VERSION 5.7 ;
  NOWIREEXTENSIONATPIN ON ;
  DIVIDERCHAR "/" ;
  BUSBITCHARS "[]" ;
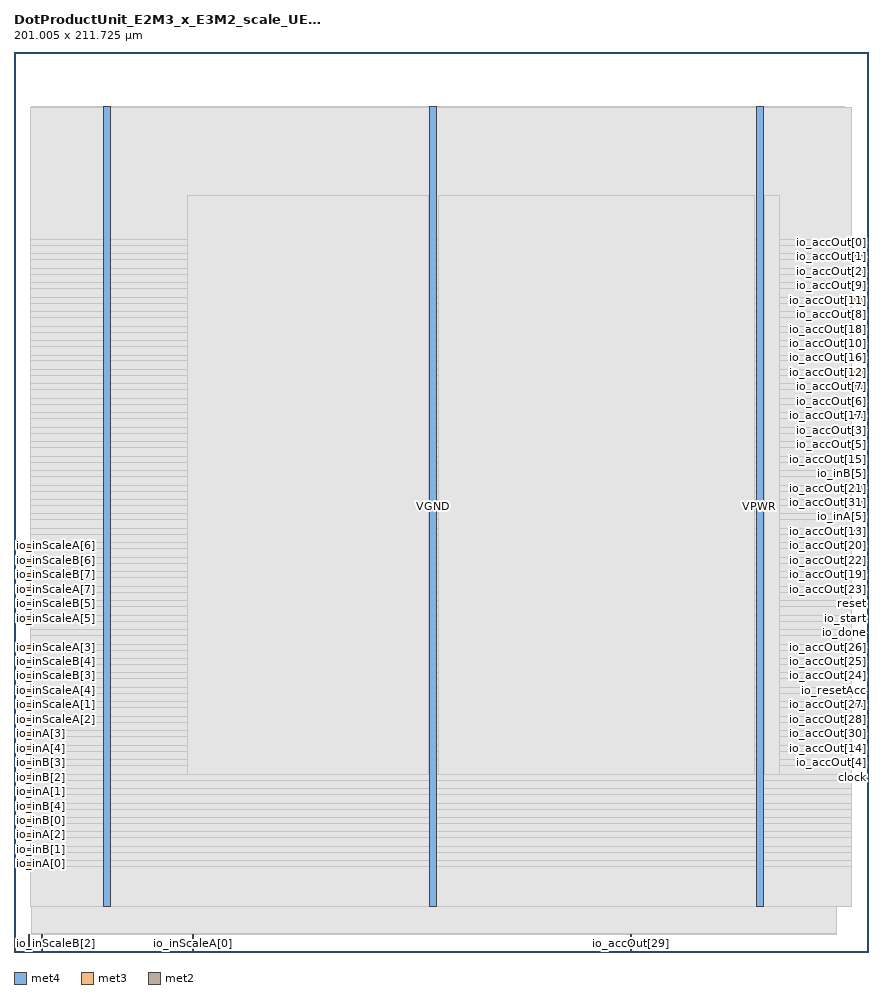
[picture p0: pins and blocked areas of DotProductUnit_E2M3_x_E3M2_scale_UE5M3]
MACRO DotProductUnit_E2M3_x_E3M2_scale_UE5M3
  CLASS BLOCK ;
  FOREIGN DotProductUnit_E2M3_x_E3M2_scale_UE5M3 ;
  ORIGIN 0.000 0.000 ;
  SIZE 201.005 BY 211.725 ;
  PIN VGND
    DIRECTION INOUT ;
    USE GROUND ;
    PORT
      LAYER met4 ;
        RECT 97.840 10.640 99.440 198.800 ;
    END
  END VGND
  PIN VPWR
    DIRECTION INOUT ;
    USE POWER ;
    PORT
      LAYER met4 ;
        RECT 21.040 10.640 22.640 198.800 ;
    END
    PORT
      LAYER met4 ;
        RECT 174.640 10.640 176.240 198.800 ;
    END
  END VPWR
  PIN clock
    DIRECTION INPUT ;
    USE SIGNAL ;
    ANTENNAGATEAREA 0.852000 ;
    PORT
      LAYER met3 ;
        RECT 197.005 40.840 201.005 41.440 ;
    END
  END clock
  PIN io_accOut[0]
    DIRECTION OUTPUT ;
    USE SIGNAL ;
    ANTENNADIFFAREA 0.445500 ;
    PORT
      LAYER met3 ;
        RECT 197.005 166.640 201.005 167.240 ;
    END
  END io_accOut[0]
  PIN io_accOut[10]
    DIRECTION OUTPUT ;
    USE SIGNAL ;
    ANTENNADIFFAREA 0.445500 ;
    PORT
      LAYER met3 ;
        RECT 197.005 142.840 201.005 143.440 ;
    END
  END io_accOut[10]
  PIN io_accOut[11]
    DIRECTION OUTPUT ;
    USE SIGNAL ;
    ANTENNADIFFAREA 0.445500 ;
    PORT
      LAYER met3 ;
        RECT 197.005 153.040 201.005 153.640 ;
    END
  END io_accOut[11]
  PIN io_accOut[12]
    DIRECTION OUTPUT ;
    USE SIGNAL ;
    ANTENNADIFFAREA 0.445500 ;
    PORT
      LAYER met3 ;
        RECT 197.005 136.040 201.005 136.640 ;
    END
  END io_accOut[12]
  PIN io_accOut[13]
    DIRECTION OUTPUT ;
    USE SIGNAL ;
    ANTENNADIFFAREA 0.445500 ;
    PORT
      LAYER met3 ;
        RECT 197.005 98.640 201.005 99.240 ;
    END
  END io_accOut[13]
  PIN io_accOut[14]
    DIRECTION OUTPUT ;
    USE SIGNAL ;
    ANTENNADIFFAREA 0.445500 ;
    PORT
      LAYER met3 ;
        RECT 197.005 47.640 201.005 48.240 ;
    END
  END io_accOut[14]
  PIN io_accOut[15]
    DIRECTION OUTPUT ;
    USE SIGNAL ;
    ANTENNADIFFAREA 0.445500 ;
    PORT
      LAYER met3 ;
        RECT 197.005 115.640 201.005 116.240 ;
    END
  END io_accOut[15]
  PIN io_accOut[16]
    DIRECTION OUTPUT ;
    USE SIGNAL ;
    ANTENNADIFFAREA 0.445500 ;
    PORT
      LAYER met3 ;
        RECT 197.005 139.440 201.005 140.040 ;
    END
  END io_accOut[16]
  PIN io_accOut[17]
    DIRECTION OUTPUT ;
    USE SIGNAL ;
    ANTENNADIFFAREA 0.445500 ;
    PORT
      LAYER met3 ;
        RECT 197.005 125.840 201.005 126.440 ;
    END
  END io_accOut[17]
  PIN io_accOut[18]
    DIRECTION OUTPUT ;
    USE SIGNAL ;
    ANTENNADIFFAREA 0.445500 ;
    PORT
      LAYER met3 ;
        RECT 197.005 146.240 201.005 146.840 ;
    END
  END io_accOut[18]
  PIN io_accOut[19]
    DIRECTION OUTPUT ;
    USE SIGNAL ;
    ANTENNADIFFAREA 0.445500 ;
    PORT
      LAYER met3 ;
        RECT 197.005 88.440 201.005 89.040 ;
    END
  END io_accOut[19]
  PIN io_accOut[1]
    DIRECTION OUTPUT ;
    USE SIGNAL ;
    ANTENNADIFFAREA 0.445500 ;
    PORT
      LAYER met3 ;
        RECT 197.005 163.240 201.005 163.840 ;
    END
  END io_accOut[1]
  PIN io_accOut[20]
    DIRECTION OUTPUT ;
    USE SIGNAL ;
    ANTENNADIFFAREA 0.445500 ;
    PORT
      LAYER met3 ;
        RECT 197.005 95.240 201.005 95.840 ;
    END
  END io_accOut[20]
  PIN io_accOut[21]
    DIRECTION OUTPUT ;
    USE SIGNAL ;
    ANTENNADIFFAREA 0.445500 ;
    PORT
      LAYER met3 ;
        RECT 197.005 108.840 201.005 109.440 ;
    END
  END io_accOut[21]
  PIN io_accOut[22]
    DIRECTION OUTPUT ;
    USE SIGNAL ;
    ANTENNADIFFAREA 0.445500 ;
    PORT
      LAYER met3 ;
        RECT 197.005 91.840 201.005 92.440 ;
    END
  END io_accOut[22]
  PIN io_accOut[23]
    DIRECTION OUTPUT ;
    USE SIGNAL ;
    ANTENNADIFFAREA 0.445500 ;
    PORT
      LAYER met3 ;
        RECT 197.005 85.040 201.005 85.640 ;
    END
  END io_accOut[23]
  PIN io_accOut[24]
    DIRECTION OUTPUT ;
    USE SIGNAL ;
    ANTENNADIFFAREA 0.445500 ;
    PORT
      LAYER met3 ;
        RECT 197.005 64.640 201.005 65.240 ;
    END
  END io_accOut[24]
  PIN io_accOut[25]
    DIRECTION OUTPUT ;
    USE SIGNAL ;
    ANTENNADIFFAREA 0.445500 ;
    PORT
      LAYER met3 ;
        RECT 197.005 68.040 201.005 68.640 ;
    END
  END io_accOut[25]
  PIN io_accOut[26]
    DIRECTION OUTPUT ;
    USE SIGNAL ;
    ANTENNADIFFAREA 0.445500 ;
    PORT
      LAYER met3 ;
        RECT 197.005 71.440 201.005 72.040 ;
    END
  END io_accOut[26]
  PIN io_accOut[27]
    DIRECTION OUTPUT ;
    USE SIGNAL ;
    ANTENNADIFFAREA 0.445500 ;
    PORT
      LAYER met3 ;
        RECT 197.005 57.840 201.005 58.440 ;
    END
  END io_accOut[27]
  PIN io_accOut[28]
    DIRECTION OUTPUT ;
    USE SIGNAL ;
    ANTENNADIFFAREA 0.445500 ;
    PORT
      LAYER met3 ;
        RECT 197.005 54.440 201.005 55.040 ;
    END
  END io_accOut[28]
  PIN io_accOut[29]
    DIRECTION OUTPUT ;
    USE SIGNAL ;
    ANTENNADIFFAREA 0.445500 ;
    PORT
      LAYER met2 ;
        RECT 144.990 0.000 145.270 4.000 ;
    END
  END io_accOut[29]
  PIN io_accOut[2]
    DIRECTION OUTPUT ;
    USE SIGNAL ;
    ANTENNADIFFAREA 0.445500 ;
    PORT
      LAYER met3 ;
        RECT 197.005 159.840 201.005 160.440 ;
    END
  END io_accOut[2]
  PIN io_accOut[30]
    DIRECTION OUTPUT ;
    USE SIGNAL ;
    ANTENNADIFFAREA 0.445500 ;
    PORT
      LAYER met3 ;
        RECT 197.005 51.040 201.005 51.640 ;
    END
  END io_accOut[30]
  PIN io_accOut[31]
    DIRECTION OUTPUT ;
    USE SIGNAL ;
    ANTENNADIFFAREA 0.445500 ;
    PORT
      LAYER met3 ;
        RECT 197.005 105.440 201.005 106.040 ;
    END
  END io_accOut[31]
  PIN io_accOut[3]
    DIRECTION OUTPUT ;
    USE SIGNAL ;
    ANTENNADIFFAREA 0.445500 ;
    PORT
      LAYER met3 ;
        RECT 197.005 122.440 201.005 123.040 ;
    END
  END io_accOut[3]
  PIN io_accOut[4]
    DIRECTION OUTPUT ;
    USE SIGNAL ;
    ANTENNADIFFAREA 0.445500 ;
    PORT
      LAYER met3 ;
        RECT 197.005 44.240 201.005 44.840 ;
    END
  END io_accOut[4]
  PIN io_accOut[5]
    DIRECTION OUTPUT ;
    USE SIGNAL ;
    ANTENNADIFFAREA 0.445500 ;
    PORT
      LAYER met3 ;
        RECT 197.005 119.040 201.005 119.640 ;
    END
  END io_accOut[5]
  PIN io_accOut[6]
    DIRECTION OUTPUT ;
    USE SIGNAL ;
    ANTENNADIFFAREA 0.445500 ;
    PORT
      LAYER met3 ;
        RECT 197.005 129.240 201.005 129.840 ;
    END
  END io_accOut[6]
  PIN io_accOut[7]
    DIRECTION OUTPUT ;
    USE SIGNAL ;
    ANTENNADIFFAREA 0.445500 ;
    PORT
      LAYER met3 ;
        RECT 197.005 132.640 201.005 133.240 ;
    END
  END io_accOut[7]
  PIN io_accOut[8]
    DIRECTION OUTPUT ;
    USE SIGNAL ;
    ANTENNADIFFAREA 0.445500 ;
    PORT
      LAYER met3 ;
        RECT 197.005 149.640 201.005 150.240 ;
    END
  END io_accOut[8]
  PIN io_accOut[9]
    DIRECTION OUTPUT ;
    USE SIGNAL ;
    ANTENNADIFFAREA 0.445500 ;
    PORT
      LAYER met3 ;
        RECT 197.005 156.440 201.005 157.040 ;
    END
  END io_accOut[9]
  PIN io_done
    DIRECTION OUTPUT ;
    USE SIGNAL ;
    ANTENNADIFFAREA 0.445500 ;
    PORT
      LAYER met3 ;
        RECT 197.005 74.840 201.005 75.440 ;
    END
  END io_done
  PIN io_inA[0]
    DIRECTION INPUT ;
    USE SIGNAL ;
    ANTENNAGATEAREA 0.196500 ;
    PORT
      LAYER met3 ;
        RECT 0.000 20.440 4.000 21.040 ;
    END
  END io_inA[0]
  PIN io_inA[1]
    DIRECTION INPUT ;
    USE SIGNAL ;
    ANTENNAGATEAREA 0.126000 ;
    PORT
      LAYER met3 ;
        RECT 0.000 37.440 4.000 38.040 ;
    END
  END io_inA[1]
  PIN io_inA[2]
    DIRECTION INPUT ;
    USE SIGNAL ;
    ANTENNAGATEAREA 0.196500 ;
    PORT
      LAYER met3 ;
        RECT 0.000 27.240 4.000 27.840 ;
    END
  END io_inA[2]
  PIN io_inA[3]
    DIRECTION INPUT ;
    USE SIGNAL ;
    ANTENNAGATEAREA 0.196500 ;
    PORT
      LAYER met3 ;
        RECT 0.000 51.040 4.000 51.640 ;
    END
  END io_inA[3]
  PIN io_inA[4]
    DIRECTION INPUT ;
    USE SIGNAL ;
    ANTENNAGATEAREA 0.196500 ;
    PORT
      LAYER met3 ;
        RECT 0.000 47.640 4.000 48.240 ;
    END
  END io_inA[4]
  PIN io_inA[5]
    DIRECTION INPUT ;
    USE SIGNAL ;
    ANTENNAGATEAREA 0.196500 ;
    PORT
      LAYER met3 ;
        RECT 197.005 102.040 201.005 102.640 ;
    END
  END io_inA[5]
  PIN io_inB[0]
    DIRECTION INPUT ;
    USE SIGNAL ;
    ANTENNAGATEAREA 0.196500 ;
    PORT
      LAYER met3 ;
        RECT 0.000 30.640 4.000 31.240 ;
    END
  END io_inB[0]
  PIN io_inB[1]
    DIRECTION INPUT ;
    USE SIGNAL ;
    ANTENNAGATEAREA 0.196500 ;
    PORT
      LAYER met3 ;
        RECT 0.000 23.840 4.000 24.440 ;
    END
  END io_inB[1]
  PIN io_inB[2]
    DIRECTION INPUT ;
    USE SIGNAL ;
    ANTENNAGATEAREA 0.495000 ;
    PORT
      LAYER met3 ;
        RECT 0.000 40.840 4.000 41.440 ;
    END
  END io_inB[2]
  PIN io_inB[3]
    DIRECTION INPUT ;
    USE SIGNAL ;
    ANTENNAGATEAREA 0.247500 ;
    PORT
      LAYER met3 ;
        RECT 0.000 44.240 4.000 44.840 ;
    END
  END io_inB[3]
  PIN io_inB[4]
    DIRECTION INPUT ;
    USE SIGNAL ;
    ANTENNAGATEAREA 0.213000 ;
    PORT
      LAYER met3 ;
        RECT 0.000 34.040 4.000 34.640 ;
    END
  END io_inB[4]
  PIN io_inB[5]
    DIRECTION INPUT ;
    USE SIGNAL ;
    ANTENNAGATEAREA 0.196500 ;
    PORT
      LAYER met3 ;
        RECT 197.005 112.240 201.005 112.840 ;
    END
  END io_inB[5]
  PIN io_inScaleA[0]
    DIRECTION INPUT ;
    USE SIGNAL ;
    ANTENNAGATEAREA 0.213000 ;
    PORT
      LAYER met2 ;
        RECT 41.950 0.000 42.230 4.000 ;
    END
  END io_inScaleA[0]
  PIN io_inScaleA[1]
    DIRECTION INPUT ;
    USE SIGNAL ;
    ANTENNAGATEAREA 0.196500 ;
    PORT
      LAYER met3 ;
        RECT 0.000 57.840 4.000 58.440 ;
    END
  END io_inScaleA[1]
  PIN io_inScaleA[2]
    DIRECTION INPUT ;
    USE SIGNAL ;
    ANTENNAGATEAREA 0.126000 ;
    PORT
      LAYER met3 ;
        RECT 0.000 54.440 4.000 55.040 ;
    END
  END io_inScaleA[2]
  PIN io_inScaleA[3]
    DIRECTION INPUT ;
    USE SIGNAL ;
    ANTENNAGATEAREA 0.196500 ;
    PORT
      LAYER met3 ;
        RECT 0.000 71.440 4.000 72.040 ;
    END
  END io_inScaleA[3]
  PIN io_inScaleA[4]
    DIRECTION INPUT ;
    USE SIGNAL ;
    ANTENNAGATEAREA 0.196500 ;
    PORT
      LAYER met3 ;
        RECT 0.000 61.240 4.000 61.840 ;
    END
  END io_inScaleA[4]
  PIN io_inScaleA[5]
    DIRECTION INPUT ;
    USE SIGNAL ;
    ANTENNAGATEAREA 0.196500 ;
    PORT
      LAYER met3 ;
        RECT 0.000 78.240 4.000 78.840 ;
    END
  END io_inScaleA[5]
  PIN io_inScaleA[6]
    DIRECTION INPUT ;
    USE SIGNAL ;
    ANTENNAGATEAREA 0.196500 ;
    PORT
      LAYER met3 ;
        RECT 0.000 95.240 4.000 95.840 ;
    END
  END io_inScaleA[6]
  PIN io_inScaleA[7]
    DIRECTION INPUT ;
    USE SIGNAL ;
    ANTENNAGATEAREA 0.196500 ;
    PORT
      LAYER met3 ;
        RECT 0.000 85.040 4.000 85.640 ;
    END
  END io_inScaleA[7]
  PIN io_inScaleB[0]
    DIRECTION INPUT ;
    USE SIGNAL ;
    PORT
      LAYER met2 ;
        RECT 0.090 0.000 0.370 4.000 ;
    END
  END io_inScaleB[0]
  PIN io_inScaleB[1]
    DIRECTION INPUT ;
    USE SIGNAL ;
    PORT
      LAYER met2 ;
        RECT 3.310 0.000 3.590 4.000 ;
    END
  END io_inScaleB[1]
  PIN io_inScaleB[2]
    DIRECTION INPUT ;
    USE SIGNAL ;
    PORT
      LAYER met2 ;
        RECT 6.530 0.000 6.810 4.000 ;
    END
  END io_inScaleB[2]
  PIN io_inScaleB[3]
    DIRECTION INPUT ;
    USE SIGNAL ;
    ANTENNAGATEAREA 0.196500 ;
    PORT
      LAYER met3 ;
        RECT 0.000 64.640 4.000 65.240 ;
    END
  END io_inScaleB[3]
  PIN io_inScaleB[4]
    DIRECTION INPUT ;
    USE SIGNAL ;
    ANTENNAGATEAREA 0.196500 ;
    PORT
      LAYER met3 ;
        RECT 0.000 68.040 4.000 68.640 ;
    END
  END io_inScaleB[4]
  PIN io_inScaleB[5]
    DIRECTION INPUT ;
    USE SIGNAL ;
    ANTENNAGATEAREA 0.196500 ;
    PORT
      LAYER met3 ;
        RECT 0.000 81.640 4.000 82.240 ;
    END
  END io_inScaleB[5]
  PIN io_inScaleB[6]
    DIRECTION INPUT ;
    USE SIGNAL ;
    ANTENNAGATEAREA 0.196500 ;
    PORT
      LAYER met3 ;
        RECT 0.000 91.840 4.000 92.440 ;
    END
  END io_inScaleB[6]
  PIN io_inScaleB[7]
    DIRECTION INPUT ;
    USE SIGNAL ;
    ANTENNAGATEAREA 0.196500 ;
    PORT
      LAYER met3 ;
        RECT 0.000 88.440 4.000 89.040 ;
    END
  END io_inScaleB[7]
  PIN io_resetAcc
    DIRECTION INPUT ;
    USE SIGNAL ;
    ANTENNAGATEAREA 0.196500 ;
    PORT
      LAYER met3 ;
        RECT 197.005 61.240 201.005 61.840 ;
    END
  END io_resetAcc
  PIN io_start
    DIRECTION INPUT ;
    USE SIGNAL ;
    ANTENNAGATEAREA 0.196500 ;
    PORT
      LAYER met3 ;
        RECT 197.005 78.240 201.005 78.840 ;
    END
  END io_start
  PIN reset
    DIRECTION INPUT ;
    USE SIGNAL ;
    ANTENNAGATEAREA 0.126000 ;
    ANTENNADIFFAREA 0.434700 ;
    PORT
      LAYER met3 ;
        RECT 197.005 81.640 201.005 82.240 ;
    END
  END reset
  OBS
      LAYER nwell ;
        RECT 5.330 10.795 195.230 198.750 ;
      LAYER li1 ;
        RECT 5.520 10.795 195.040 198.645 ;
      LAYER met1 ;
        RECT 4.210 10.640 195.340 198.800 ;
      LAYER met2 ;
        RECT 4.230 4.280 193.570 198.745 ;
        RECT 4.230 4.000 6.250 4.280 ;
        RECT 7.090 4.000 41.670 4.280 ;
        RECT 42.510 4.000 144.710 4.280 ;
        RECT 145.550 4.000 193.570 4.280 ;
      LAYER met3 ;
        RECT 3.990 167.640 197.005 198.725 ;
        RECT 3.990 166.240 196.605 167.640 ;
        RECT 3.990 164.240 197.005 166.240 ;
        RECT 3.990 162.840 196.605 164.240 ;
        RECT 3.990 160.840 197.005 162.840 ;
        RECT 3.990 159.440 196.605 160.840 ;
        RECT 3.990 157.440 197.005 159.440 ;
        RECT 3.990 156.040 196.605 157.440 ;
        RECT 3.990 154.040 197.005 156.040 ;
        RECT 3.990 152.640 196.605 154.040 ;
        RECT 3.990 150.640 197.005 152.640 ;
        RECT 3.990 149.240 196.605 150.640 ;
        RECT 3.990 147.240 197.005 149.240 ;
        RECT 3.990 145.840 196.605 147.240 ;
        RECT 3.990 143.840 197.005 145.840 ;
        RECT 3.990 142.440 196.605 143.840 ;
        RECT 3.990 140.440 197.005 142.440 ;
        RECT 3.990 139.040 196.605 140.440 ;
        RECT 3.990 137.040 197.005 139.040 ;
        RECT 3.990 135.640 196.605 137.040 ;
        RECT 3.990 133.640 197.005 135.640 ;
        RECT 3.990 132.240 196.605 133.640 ;
        RECT 3.990 130.240 197.005 132.240 ;
        RECT 3.990 128.840 196.605 130.240 ;
        RECT 3.990 126.840 197.005 128.840 ;
        RECT 3.990 125.440 196.605 126.840 ;
        RECT 3.990 123.440 197.005 125.440 ;
        RECT 3.990 122.040 196.605 123.440 ;
        RECT 3.990 120.040 197.005 122.040 ;
        RECT 3.990 118.640 196.605 120.040 ;
        RECT 3.990 116.640 197.005 118.640 ;
        RECT 3.990 115.240 196.605 116.640 ;
        RECT 3.990 113.240 197.005 115.240 ;
        RECT 3.990 111.840 196.605 113.240 ;
        RECT 3.990 109.840 197.005 111.840 ;
        RECT 3.990 108.440 196.605 109.840 ;
        RECT 3.990 106.440 197.005 108.440 ;
        RECT 3.990 105.040 196.605 106.440 ;
        RECT 3.990 103.040 197.005 105.040 ;
        RECT 3.990 101.640 196.605 103.040 ;
        RECT 3.990 99.640 197.005 101.640 ;
        RECT 3.990 98.240 196.605 99.640 ;
        RECT 3.990 96.240 197.005 98.240 ;
        RECT 4.400 94.840 196.605 96.240 ;
        RECT 3.990 92.840 197.005 94.840 ;
        RECT 4.400 91.440 196.605 92.840 ;
        RECT 3.990 89.440 197.005 91.440 ;
        RECT 4.400 88.040 196.605 89.440 ;
        RECT 3.990 86.040 197.005 88.040 ;
        RECT 4.400 84.640 196.605 86.040 ;
        RECT 3.990 82.640 197.005 84.640 ;
        RECT 4.400 81.240 196.605 82.640 ;
        RECT 3.990 79.240 197.005 81.240 ;
        RECT 4.400 77.840 196.605 79.240 ;
        RECT 3.990 75.840 197.005 77.840 ;
        RECT 3.990 74.440 196.605 75.840 ;
        RECT 3.990 72.440 197.005 74.440 ;
        RECT 4.400 71.040 196.605 72.440 ;
        RECT 3.990 69.040 197.005 71.040 ;
        RECT 4.400 67.640 196.605 69.040 ;
        RECT 3.990 65.640 197.005 67.640 ;
        RECT 4.400 64.240 196.605 65.640 ;
        RECT 3.990 62.240 197.005 64.240 ;
        RECT 4.400 60.840 196.605 62.240 ;
        RECT 3.990 58.840 197.005 60.840 ;
        RECT 4.400 57.440 196.605 58.840 ;
        RECT 3.990 55.440 197.005 57.440 ;
        RECT 4.400 54.040 196.605 55.440 ;
        RECT 3.990 52.040 197.005 54.040 ;
        RECT 4.400 50.640 196.605 52.040 ;
        RECT 3.990 48.640 197.005 50.640 ;
        RECT 4.400 47.240 196.605 48.640 ;
        RECT 3.990 45.240 197.005 47.240 ;
        RECT 4.400 43.840 196.605 45.240 ;
        RECT 3.990 41.840 197.005 43.840 ;
        RECT 4.400 40.440 196.605 41.840 ;
        RECT 3.990 38.440 197.005 40.440 ;
        RECT 4.400 37.040 197.005 38.440 ;
        RECT 3.990 35.040 197.005 37.040 ;
        RECT 4.400 33.640 197.005 35.040 ;
        RECT 3.990 31.640 197.005 33.640 ;
        RECT 4.400 30.240 197.005 31.640 ;
        RECT 3.990 28.240 197.005 30.240 ;
        RECT 4.400 26.840 197.005 28.240 ;
        RECT 3.990 24.840 197.005 26.840 ;
        RECT 4.400 23.440 197.005 24.840 ;
        RECT 3.990 21.440 197.005 23.440 ;
        RECT 4.400 20.040 197.005 21.440 ;
        RECT 3.990 10.715 197.005 20.040 ;
      LAYER met4 ;
        RECT 40.775 41.655 97.440 177.985 ;
        RECT 99.840 41.655 174.240 177.985 ;
        RECT 176.640 41.655 180.025 177.985 ;
  END
END DotProductUnit_E2M3_x_E3M2_scale_UE5M3
END LIBRARY

